# LEF file generated by Abstract Generator version 5.5.12 on Aug 29 09:17:23 2003
#
# Contains LEF for bin Corner.
# Options:   [ ] Antenna
#            [x] Geometry
#            [x] Technology

VERSION 5.3 ;
NAMESCASESENSITIVE ON ;
BUSBITCHARS "[]" ;
DIVIDERCHAR "/" ;
UNITS
  DATABASE MICRONS 1000 ;
END UNITS

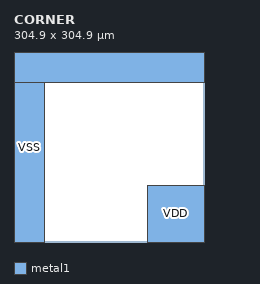
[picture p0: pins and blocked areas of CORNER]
MACRO CORNER
  CLASS  ENDCAP TOPLEFT ;
  FOREIGN CORNER 0.000 0.000 ;
  ORIGIN 0.000 0.000 ;
  SIZE 304.900 BY 304.900 ;
  SYMMETRY X Y R90  ;
  SITE corner ;
  PIN VSS
    DIRECTION INOUT ;
    USE GROUND ;
    SHAPE FEEDTHRU ;
    PORT
      
      LAYER metal1 ;
        RECT 0.000 0.000 48.700 304.900 ;
        RECT 0.000 256.200 304.900 304.900 ;
    END
  END VSS
  PIN VDD
    DIRECTION INOUT ;
    USE POWER ;
    SHAPE FEEDTHRU ;
    PORT
      LAYER metal1 ;
        RECT 214.200 0.000 304.900 90.700 ;
    END
  END VDD
  OBS 
   LAYER metal2 ;
        RECT 0.000 0.000 48.700 304.900 ;
        RECT 0.000 256.200 304.900 304.900 ;   
  END 
END CORNER

END LIBRARY
